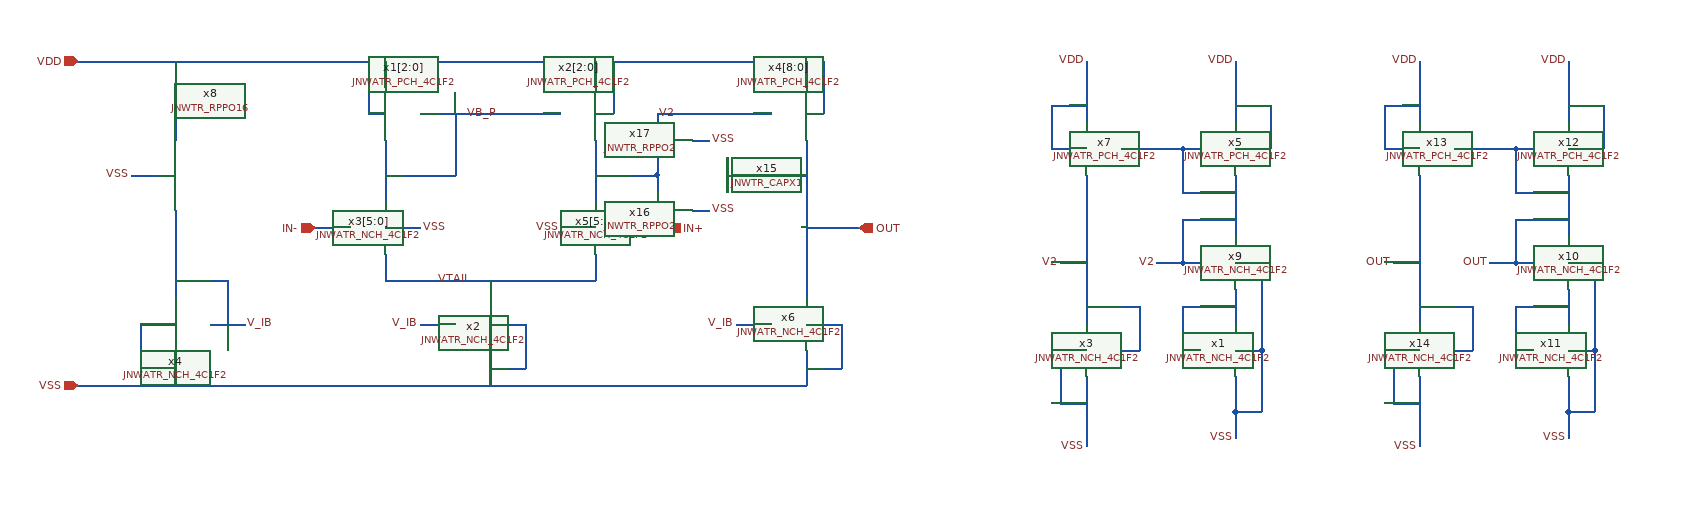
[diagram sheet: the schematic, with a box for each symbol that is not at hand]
v {xschem version=3.4.7 file_version=1.2}
G {}
K {}
V {}
S {}
E {}
N -120 -20 -120 50 {lab=VB_P}
N -120 20 -40 20 {lab=VB_P}
N -40 -50 -40 20 {lab=VB_P}
N -80 -50 80 -50 {lab=VB_P}
N 120 -20 120 50 {lab=V2}
N 120 110 120 140 {lab=VTAIL}
N -120 140 120 140 {lab=VTAIL}
N -120 110 -120 140 {lab=VTAIL}
N -120 -110 -120 -80 {lab=VDD}
N 120 -110 120 -80 {lab=VDD}
N -0 140 -0 160 {lab=VTAIL}
N -200 80 -160 80 {lab=IN-}
N 160 80 200 80 {lab=IN+}
N -140 -50 -120 -50 {lab=VDD}
N -140 -110 -140 -50 {lab=VDD}
N 120 -50 140 -50 {lab=VDD}
N 140 -110 140 -50 {lab=VDD}
N -80 190 -40 190 {lab=V_IB}
N -320 190 -280 190 {lab=V_IB}
N -300 140 -300 190 {lab=V_IB}
N -360 140 -300 140 {lab=V_IB}
N -400 190 -360 190 {lab=VSS}
N -400 190 -400 240 {lab=VSS}
N -400 240 -360 240 {lab=VSS}
N -360 220 -360 260 {lab=VSS}
N 0 220 0 260 {lab=VSS}
N 0 190 40 190 {lab=VSS}
N 40 190 40 240 {lab=VSS}
N -0 240 40 240 {lab=VSS}
N -120 80 -80 80 {lab=VSS}
N 80 80 120 80 {lab=VSS}
N 190 -50 190 20 {lab=V2}
N 380 -110 380 -50 {lab=VDD}
N 360 -50 380 -50 {lab=VDD}
N 360 -110 360 -80 {lab=VDD}
N 280 190 320 190 {lab=V_IB}
N 360 220 360 260 {lab=VSS}
N 360 240 400 240 {lab=VSS}
N 400 190 400 240 {lab=VSS}
N 360 190 400 190 {lab=VSS}
N 360 80 420 80 {lab=OUT}
N -360 60 -360 160 {lab=V_IB}
N 360 -20 360 160 {lab=OUT}
N -470 260 360 260 {lab=VSS}
N -470 -110 380 -110 {lab=VDD}
N 790 120 810 120 {lab=V2}
N 790 70 790 120 {lab=V2}
N 790 70 850 70 {lab=V2}
N 850 150 850 190 {lab=#net1}
N 850 120 880 120 {lab=VSS}
N 880 120 880 170 {lab=VSS}
N 760 120 790 120 {lab=V2}
N 790 220 810 220 {lab=#net1}
N 790 170 790 220 {lab=#net1}
N 790 170 850 170 {lab=#net1}
N 850 250 850 290 {lab=VSS}
N 850 220 880 220 {lab=VSS}
N 880 220 880 270 {lab=VSS}
N 880 170 880 220 {lab=VSS}
N 880 270 880 290 {lab=VSS}
N 850 290 880 290 {lab=VSS}
N 850 290 850 320 {lab=VSS}
N 850 20 850 90 {lab=V2}
N 850 -110 850 -40 {lab=VDD}
N 790 -10 810 -10 {lab=V2}
N 790 -10 790 40 {lab=V2}
N 790 40 850 40 {lab=V2}
N 680 -110 680 -40 {lab=VDD}
N 650 120 680 120 {lab=V2}
N 720 -10 790 -10 {lab=V2}
N 680 250 680 330 {lab=VSS}
N 650 220 680 220 {lab=VSS}
N 650 220 650 280 {lab=VSS}
N 650 280 680 280 {lab=VSS}
N 720 220 740 220 {lab=V2}
N 740 170 740 220 {lab=V2}
N 680 170 740 170 {lab=V2}
N 680 20 680 190 {lab=V2}
N 640 -10 680 -10 {lab=VDD}
N 640 -60 640 -10 {lab=VDD}
N 640 -60 680 -60 {lab=VDD}
N 850 -10 890 -10 {lab=VDD}
N 890 -60 890 -10 {lab=VDD}
N 850 -60 890 -60 {lab=VDD}
N -360 -110 -360 -20 {lab=VDD}
N -410 20 -380 20 {lab=VSS}
N 1170 120 1190 120 {lab=OUT}
N 1170 70 1170 120 {lab=OUT}
N 1170 70 1230 70 {lab=OUT}
N 1230 150 1230 190 {lab=#net2}
N 1230 120 1260 120 {lab=VSS}
N 1260 120 1260 170 {lab=VSS}
N 1140 120 1170 120 {lab=OUT}
N 1170 220 1190 220 {lab=#net2}
N 1170 170 1170 220 {lab=#net2}
N 1170 170 1230 170 {lab=#net2}
N 1230 250 1230 290 {lab=VSS}
N 1230 220 1260 220 {lab=VSS}
N 1260 220 1260 270 {lab=VSS}
N 1260 170 1260 220 {lab=VSS}
N 1260 270 1260 290 {lab=VSS}
N 1230 290 1260 290 {lab=VSS}
N 1230 290 1230 320 {lab=VSS}
N 1230 20 1230 90 {lab=OUT}
N 1230 -110 1230 -40 {lab=VDD}
N 1170 -10 1190 -10 {lab=OUT}
N 1170 -10 1170 40 {lab=OUT}
N 1170 40 1230 40 {lab=OUT}
N 1060 -110 1060 -40 {lab=VDD}
N 1030 120 1060 120 {lab=OUT}
N 1100 -10 1170 -10 {lab=OUT}
N 1060 250 1060 330 {lab=VSS}
N 1030 220 1060 220 {lab=VSS}
N 1030 220 1030 280 {lab=VSS}
N 1030 280 1060 280 {lab=VSS}
N 1100 220 1120 220 {lab=OUT}
N 1120 170 1120 220 {lab=OUT}
N 1060 170 1120 170 {lab=OUT}
N 1060 20 1060 190 {lab=OUT}
N 1020 -10 1060 -10 {lab=VDD}
N 1020 -60 1020 -10 {lab=VDD}
N 1020 -60 1060 -60 {lab=VDD}
N 1230 -10 1270 -10 {lab=VDD}
N 1270 -60 1270 -10 {lab=VDD}
N 1230 -60 1270 -60 {lab=VDD}
N 190 -50 320 -50 {lab=V2}
N 350 20 360 20 {lab=OUT}
N 270 20 280 20 {lab=#net3}
N 120 20 190 20 {lab=V2}
N 190 20 190 40 {lab=V2}
N 230 60 250 60 {lab=VSS}
N 270 0 270 40 {lab=#net3}
N 230 -20 250 -20 {lab=VSS}
C {devices/lab_wire.sym} -80 190 0 0 {name=p3 sig_type=std_logic lab=V_IB}
C {devices/lab_wire.sym} -280 190 0 1 {name=p8 sig_type=std_logic lab=V_IB}
C {devices/lab_wire.sym} -80 80 2 0 {name=p16 sig_type=std_logic lab=VSS}
C {devices/lab_wire.sym} 10 -50 0 0 {name=p14 sig_type=std_logic lab=VB_P}
C {devices/lab_wire.sym} -20 140 0 0 {name=p17 sig_type=std_logic lab=VTAIL}
C {JNW_ATR_SKY130A/JNWATR_NCH_4C1F2.sym} -160 80 0 0 {name=x3[5:0]}
C {JNW_ATR_SKY130A/JNWATR_NCH_4C1F2.sym} 160 80 0 1 {name=x5[5:0]}
C {JNW_ATR_SKY130A/JNWATR_NCH_4C1F2.sym} -40 190 0 0 {name=x2}
C {JNW_ATR_SKY130A/JNWATR_NCH_4C1F2.sym} -320 190 0 1 {name=x4}
C {JNW_ATR_SKY130A/JNWATR_NCH_4C1F2.sym} 320 190 0 0 {name=x6}
C {devices/lab_wire.sym} 280 190 0 0 {name=p20 sig_type=std_logic lab=V_IB}
C {devices/lab_wire.sym} 190 -50 0 1 {name=p22 sig_type=std_logic lab=V2}
C {JNW_ATR_SKY130A/JNWATR_PCH_4C1F2.sym} 320 -50 0 0 {name=x4[8:0]}
C {JNW_ATR_SKY130A/JNWATR_PCH_4C1F2.sym} -80 -50 0 1 {name=x1[2:0]}
C {JNW_ATR_SKY130A/JNWATR_PCH_4C1F2.sym} 80 -50 0 0 {name=x2[2:0]}
C {devices/ipin.sym} -200 80 0 0 {name=p4 lab=IN-}
C {devices/opin.sym} 420 80 0 0 {name=p9 lab=OUT}
C {devices/ipin.sym} 200 80 0 1 {name=p2 lab=IN+}
C {devices/ipin.sym} -470 260 0 0 {name=p1 lab=VSS}
C {devices/ipin.sym} -470 -110 0 0 {name=p5 lab=VDD}
C {devices/lab_wire.sym} 80 80 2 1 {name=p6 sig_type=std_logic lab=VSS}
C {devices/lab_wire.sym} 850 -110 0 0 {name=p15 sig_type=std_logic lab=VDD}
C {JNW_ATR_SKY130A/JNWATR_NCH_4C1F2.sym} 810 120 0 0 {name=x9}
C {devices/lab_wire.sym} 760 120 0 0 {name=p19 sig_type=std_logic lab=V2}
C {JNW_ATR_SKY130A/JNWATR_NCH_4C1F2.sym} 810 220 0 0 {name=x1}
C {devices/lab_wire.sym} 850 320 2 1 {name=p7 sig_type=std_logic lab=VSS}
C {JNW_ATR_SKY130A/JNWATR_PCH_4C1F2.sym} 810 -10 0 0 {name=x5}
C {devices/lab_wire.sym} 680 -110 0 0 {name=p10 sig_type=std_logic lab=VDD}
C {JNW_ATR_SKY130A/JNWATR_PCH_4C1F2.sym} 720 -10 0 1 {name=x7}
C {devices/lab_wire.sym} 650 120 0 0 {name=p11 sig_type=std_logic lab=V2}
C {JNW_ATR_SKY130A/JNWATR_NCH_4C1F2.sym} 720 220 0 1 {name=x3}
C {devices/lab_wire.sym} 680 330 2 1 {name=p12 sig_type=std_logic lab=VSS}
C {JNW_TR_SKY130A/JNWTR_RPPO16.sym} -360 -20 1 0 {name=x8 }
C {devices/lab_wire.sym} -410 20 2 1 {name=p13 sig_type=std_logic lab=VSS}
C {devices/lab_wire.sym} 1230 -110 0 0 {name=p18 sig_type=std_logic lab=VDD}
C {JNW_ATR_SKY130A/JNWATR_NCH_4C1F2.sym} 1190 120 0 0 {name=x10}
C {devices/lab_wire.sym} 1140 120 0 0 {name=p21 sig_type=std_logic lab=OUT}
C {JNW_ATR_SKY130A/JNWATR_NCH_4C1F2.sym} 1190 220 0 0 {name=x11}
C {devices/lab_wire.sym} 1230 320 2 1 {name=p23 sig_type=std_logic lab=VSS}
C {JNW_ATR_SKY130A/JNWATR_PCH_4C1F2.sym} 1190 -10 0 0 {name=x12}
C {devices/lab_wire.sym} 1060 -110 0 0 {name=p24 sig_type=std_logic lab=VDD}
C {JNW_ATR_SKY130A/JNWATR_PCH_4C1F2.sym} 1100 -10 0 1 {name=x13}
C {devices/lab_wire.sym} 1030 120 0 0 {name=p25 sig_type=std_logic lab=OUT}
C {JNW_ATR_SKY130A/JNWATR_NCH_4C1F2.sym} 1100 220 0 1 {name=x14}
C {devices/lab_wire.sym} 1060 330 2 1 {name=p26 sig_type=std_logic lab=VSS}
C {JNW_TR_SKY130A/JNWTR_CAPX1.sym} 290 20 1 0 {name=x15 }
C {JNW_TR_SKY130A/JNWTR_RPPO2.sym} 190 40 0 0 {name=x16 }
C {JNW_TR_SKY130A/JNWTR_RPPO2.sym} 190 0 2 1 {name=x17 }
C {devices/lab_wire.sym} 250 60 2 0 {name=p27 sig_type=std_logic lab=VSS}
C {devices/lab_wire.sym} 250 -20 2 0 {name=p28 sig_type=std_logic lab=VSS}
